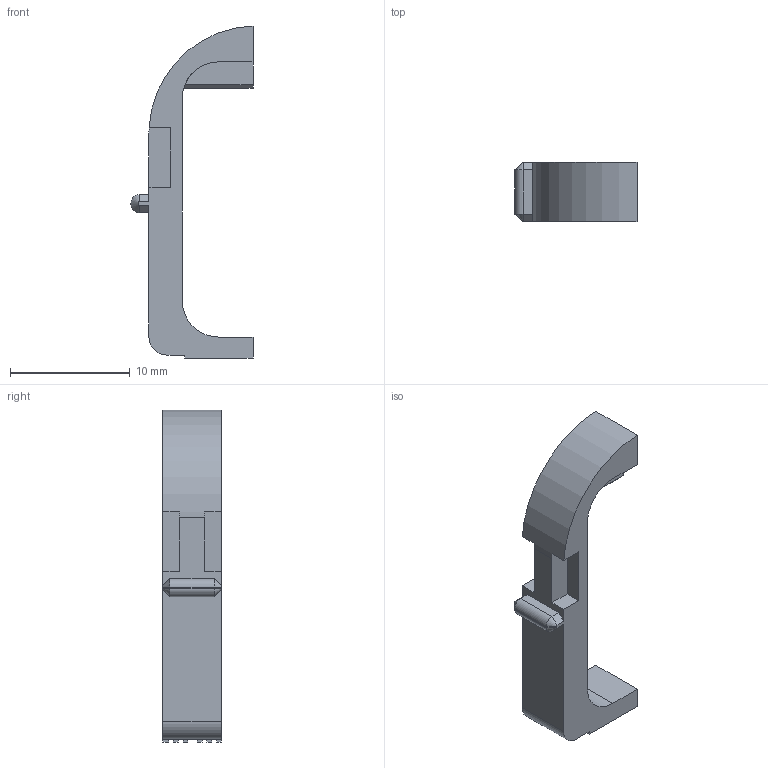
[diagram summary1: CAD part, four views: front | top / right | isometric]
STEP (ISO 10303-21) file: header records copied from the file, then geometry measured from it (millimetres).
FILE_DESCRIPTION(('HOOPS Exchange Step'),'2;1');
FILE_NAME('/private/var/mobile/Containers/Data/Application/242B779B-612D-491A-9684-5FFB86C0E403/tmp/export/temp_export','2021-04-14T10:43:11-04:00',('mobile'),('Shapr3D Limited'),'HOOPS Exchange 2020.2','Shapr3D','Authorized');
FILE_SCHEMA( ('AP203_CONFIGURATION_CONTROLLED_3D_DESIGN_OF_MECHANICAL_PARTS_AND_ASSEMBLIES_MIM_LF') );
Length unit declared in the file: millimetre
Products named in the file (1): /private/var/mobile/Containers/Data/Application/242B779B-612D-491A-9684-5FFB86C0E403/tmp/A82B3C57-F3B7-4AF7-8015-5BD69338D8A0.tmp
Bounding box: 10.2 x 4.9 x 27.75 mm (x, y, z)
Volume: 444.5 mm3; surface area: 621 mm2
Topology: 1 solids, 1 shells, 65 faces, 181 edges, 118 vertices
Faces by surface type: plane 52, cylinder 6, cone 4, bspline 3
Entity records: 2106 total; most frequent: CARTESIAN_POINT 413, ORIENTED_EDGE 362, DIRECTION 324, EDGE_CURVE 181, VECTOR 154, LINE 154, VERTEX_POINT 118, AXIS2_PLACEMENT_3D 85
One B-rep face of a CAD part: STEP entity #404.
In plain terms, the cylindrical face has radius 9 mm (diameter 18 mm), a partial arc.
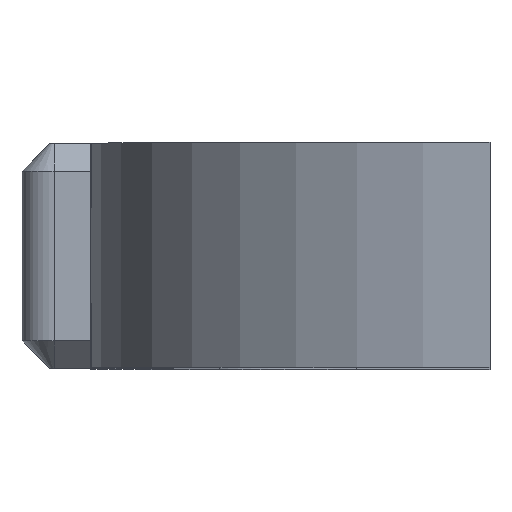
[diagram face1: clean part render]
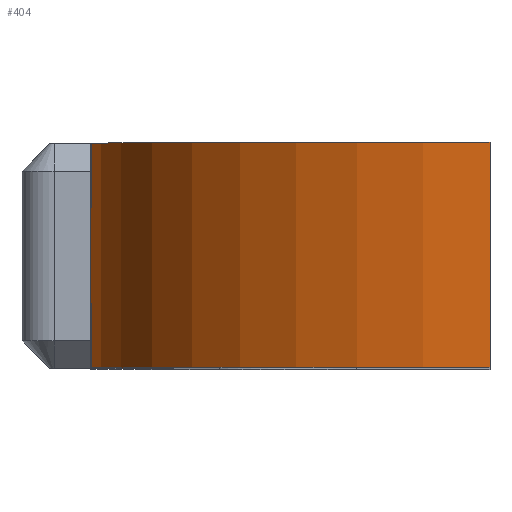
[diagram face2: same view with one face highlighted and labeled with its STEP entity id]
Its self-contained STEP definition (entity closure, numbers rounded to 3 decimals):
#40=CARTESIAN_POINT('',(-1.986,2.9,19.));
#41=VERTEX_POINT('',#40);
#59=CARTESIAN_POINT('',(-1.986,1.5,19.));
#60=VERTEX_POINT('',#59);
#68=CARTESIAN_POINT('',(-1.986,1.5,19.));
#69=DIRECTION('',(0.,1.,0.));
#70=VECTOR('',#69,1.4);
#71=LINE('',#68,#70);
#72=EDGE_CURVE('',#60,#41,#71,.T.);
#264=CARTESIAN_POINT('',(6.7,-2.,27.5));
#265=VERTEX_POINT('',#264);
#272=CARTESIAN_POINT('',(-1.986,-2.,19.));
#273=VERTEX_POINT('',#272);
#274=CARTESIAN_POINT('',(7.,-2.,18.505));
#275=DIRECTION('',(0.,-1.,0.));
#276=DIRECTION('',(1.,0.,0.));
#277=AXIS2_PLACEMENT_3D('',#274,#275,#276);
#278=CIRCLE('',#277,9.);
#279=EDGE_CURVE('',#265,#273,#278,.T.);
#348=CARTESIAN_POINT('',(7.,0.,18.505));
#349=DIRECTION('',(0.,1.,0.));
#350=DIRECTION('',(0.,-0.,1.));
#351=AXIS2_PLACEMENT_3D('',#348,#349,#350);
#352=CYLINDRICAL_SURFACE('',#351,9.);
#353=CARTESIAN_POINT('',(-1.986,-0.6,19.));
#354=VERTEX_POINT('',#353);
#355=CARTESIAN_POINT('',(-2.,-0.6,18.505));
#356=VERTEX_POINT('',#355);
#357=CARTESIAN_POINT('',(7.,-0.6,18.505));
#358=DIRECTION('',(0.,-1.,0.));
#359=DIRECTION('',(0.,0.,-1.));
#360=AXIS2_PLACEMENT_3D('',#357,#358,#359);
#361=CIRCLE('',#360,9.);
#362=EDGE_CURVE('',#354,#356,#361,.T.);
#363=ORIENTED_EDGE('',*,*,#362,.F.);
#364=CARTESIAN_POINT('',(-1.986,-0.6,19.));
#365=DIRECTION('',(0.,-1.,0.));
#366=VECTOR('',#365,1.4);
#367=LINE('',#364,#366);
#368=EDGE_CURVE('',#354,#273,#367,.T.);
#369=ORIENTED_EDGE('',*,*,#368,.T.);
#370=ORIENTED_EDGE('',*,*,#279,.F.);
#371=CARTESIAN_POINT('',(6.7,2.9,27.5));
#372=VERTEX_POINT('',#371);
#373=CARTESIAN_POINT('',(6.7,2.9,27.5));
#374=DIRECTION('',(0.,-1.,0.));
#375=VECTOR('',#374,4.9);
#376=LINE('',#373,#375);
#377=EDGE_CURVE('',#372,#265,#376,.T.);
#378=ORIENTED_EDGE('',*,*,#377,.F.);
#379=CARTESIAN_POINT('',(7.,2.9,18.505));
#380=DIRECTION('',(0.,1.,0.));
#381=DIRECTION('',(0.,-0.,1.));
#382=AXIS2_PLACEMENT_3D('',#379,#380,#381);
#383=CIRCLE('',#382,9.);
#384=EDGE_CURVE('',#41,#372,#383,.T.);
#385=ORIENTED_EDGE('',*,*,#384,.F.);
#386=ORIENTED_EDGE('',*,*,#72,.F.);
#387=CARTESIAN_POINT('',(-2.,1.5,18.505));
#388=VERTEX_POINT('',#387);
#389=CARTESIAN_POINT('',(7.,1.5,18.505));
#390=DIRECTION('',(0.,1.,0.));
#391=DIRECTION('',(0.,-0.,1.));
#392=AXIS2_PLACEMENT_3D('',#389,#390,#391);
#393=CIRCLE('',#392,9.);
#394=EDGE_CURVE('',#388,#60,#393,.T.);
#395=ORIENTED_EDGE('',*,*,#394,.F.);
#396=CARTESIAN_POINT('',(-2.,-0.6,18.505));
#397=DIRECTION('',(-0.,1.,-0.));
#398=VECTOR('',#397,2.1);
#399=LINE('',#396,#398);
#400=EDGE_CURVE('',#356,#388,#399,.T.);
#401=ORIENTED_EDGE('',*,*,#400,.F.);
#402=EDGE_LOOP('',(#363,#369,#370,#378,#385,#386,#395,#401));
#403=FACE_BOUND('',#402,.T.);
#404=ADVANCED_FACE('',(#403),#352,.T.);
